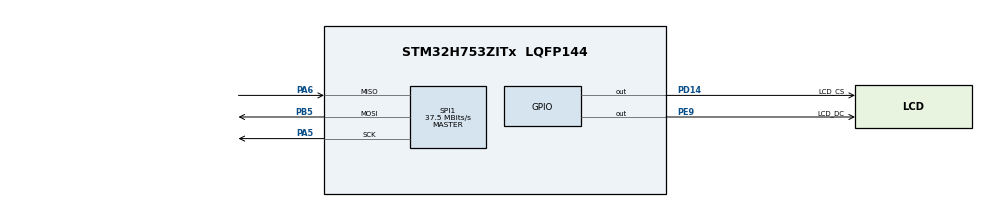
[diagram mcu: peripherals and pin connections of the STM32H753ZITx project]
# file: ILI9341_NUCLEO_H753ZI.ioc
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CORTEX_M7.CPU_DCache=Disabled
CORTEX_M7.CPU_ICache=Disabled
CORTEX_M7.MPU_Control=__NULL
CORTEX_M7.default_mode_Activation=1
Mcu.Family=STM32H7
Mcu.Name=STM32H753ZITx
Mcu.Package=LQFP144
NUCLEO-H753ZI.VCP=true
NVIC.PriorityGroup=NVIC_PRIORITYGROUP_4
NVIC.TIM6_DAC_IRQn=true\:0\:0\:false\:false\:true\:true\:true\:true
PA5.Mode=Full_Duplex_Master
PA5.Signal=SPI1_SCK
PA6.Mode=Full_Duplex_Master
PA6.Signal=SPI1_MISO
PB5.Mode=Full_Duplex_Master
PB5.Signal=SPI1_MOSI
PC14-OSC32_IN\ (OSC32_IN).Signal=RCC_OSC32_IN
PC15-OSC32_OUT\ (OSC32_OUT).Signal=RCC_OSC32_OUT
PD14.GPIO_Label=LCD_CS
PD14.Signal=GPIO_Output
PD8.Signal=USART3_TX
PD9.Signal=USART3_RX
PE9.GPIO_Label=LCD_DC
PE9.Signal=GPIO_Output
PH0-OSC_IN\ (PH0).Signal=RCC_OSC_IN
PH1-OSC_OUT\ (PH1).Signal=RCC_OSC_OUT
ProjectManager.HeapSize=0x200
ProjectManager.StackSize=0x400
ProjectManager.TargetToolchain=STM32CubeIDE
RCC.ADCFreq_Value=129000000
RCC.APB1Freq_Value=64000000
RCC.APB2Freq_Value=64000000
RCC.APB3Freq_Value=64000000
RCC.APB4Freq_Value=64000000
RCC.CortexFreq_Value=64000000
RCC.DIVM1=4
RCC.DIVN1=9
RCC.DIVQ1=1
RCC.HCLKFreq_Value=64000000
RCC.HSE_VALUE=8000000
RCC.PLLFRACN=3072
RCC.PWR_Regulator_Voltage_Scale=PWR_REGULATOR_VOLTAGE_SCALE2
RCC.SYSCLKFreq_VALUE=64000000
RCC.USBFreq_Value=150000000
SPI1.BaudRatePrescaler=SPI_BAUDRATEPRESCALER_4
SPI1.CalculateBaudRate=37.5 MBits/s
SPI1.DataSize=SPI_DATASIZE_8BIT
SPI1.Direction=SPI_DIRECTION_2LINES
SPI1.MasterKeepIOState=SPI_MASTER_KEEP_IO_STATE_ENABLE
SPI1.MasterReceiverAutoSusp=SPI_MASTER_RX_AUTOSUSP_ENABLE
SPI1.Mode=SPI_MODE_MASTER
SPI1.NSSPMode=SPI_NSS_PULSE_DISABLE
SPI1.VirtualType=VM_MASTER
TIM6.Period=999
TIM6.Prescaler=63
VP_MEMORYMAP_VS_MEMORYMAP.Mode=CurAppReg
VP_NUCLEO-H753ZI_VS_BSP_COMMON.Mode=COMMON
VP_TIM6_VS_ClockSourceINT.Mode=Enable_Timer
board=NUCLEO-H753ZI

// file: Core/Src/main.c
/* USER CODE BEGIN Header */
/**
  ******************************************************************************
  * @file           : main.c
  * @brief          : Main program body
  ******************************************************************************
  * @attention
  *
  * Copyright (c) 2026 STMicroelectronics.
  * All rights reserved.
  *
  * This software is licensed under terms that can be found in the LICENSE file
  * in the root directory of this software component.
  * If no LICENSE file comes with this software, it is provided AS-IS.
  *
  ******************************************************************************
  */
/* USER CODE END Header */
#include "main.h"

/* USER CODE BEGIN Includes */

#include "ili9341.h"

#include "lvgl.h"
#include "demos/lv_demos.h"

/* USER CODE END Includes */

/* USER CODE BEGIN PM */

#define LCD_WIDTH             	320
#define LCD_HEIGHT            	240

#define CHUNK_SIZE (LCD_HEIGHT * LCD_WIDTH / 3)

#define LCD_FB_BYTE_PER_PIXEL 	2
/* Max DMA transfer = 65535 bytes (uint16_t). 320*102*2 = 65280 bytes. */
#define LCD_VIRTUAL_BUF_SIZE (LCD_WIDTH * 102)

// RGB565 color format: 16-bit
#define COLOR_RED   0xF800
#define COLOR_BLUE  0x001F

/* USER CODE END PM */

COM_InitTypeDef BspCOMInit;

SPI_HandleTypeDef hspi1;

TIM_HandleTypeDef htim6;

/* USER CODE BEGIN PV */

uint8_t buffer[CHUNK_SIZE];

/* Align to 32 bytes for D-Cache / DMA coherency */
static uint8_t s_frameBuffer[2][LCD_VIRTUAL_BUF_SIZE * LCD_FB_BYTE_PER_PIXEL] __attribute__((aligned(32)));

/* USER CODE END PV */

void SystemClock_Config(void);
static void MX_GPIO_Init(void);
static void MX_SPI1_Init(void);
static void MX_TIM6_Init(void);
/* USER CODE BEGIN PFP */

void LCD_Init();
void LCD_Test();

#ifdef __cplusplus
extern "C" {
#endif

void lv_port_disp_init(void);
void lv_port_indev_init(void);

#if defined(__cplusplus)
}
#endif

/* USER CODE END PFP */

int main(void)
{

  /* USER CODE BEGIN 1 */
  SCB_EnableICache();
  SCB_EnableDCache();
  /* USER CODE END 1 */

  /* MCU Configuration--------------------------------------------------------*/

  /* Reset of all peripherals, Initializes the Flash interface and the Systick. */
  HAL_Init();

  /* Configure the system clock */
  SystemClock_Config();

  /* Initialize all configured peripherals */
  MX_GPIO_Init();
  MX_SPI1_Init();
  MX_TIM6_Init();
  /* USER CODE BEGIN 2 */

  HAL_TIM_Base_Start_IT(&htim6);

  LCD_Init();

  lv_init();
  lv_port_disp_init();

  /* USER CODE END 2 */

  /* Initialize COM1 port (115200, 8 bits (7-bit data + 1 stop bit), no parity */
  BspCOMInit.BaudRate   = 115200;
  BspCOMInit.WordLength = COM_WORDLENGTH_8B;
  BspCOMInit.StopBits   = COM_STOPBITS_1;
  BspCOMInit.Parity     = COM_PARITY_NONE;
  BspCOMInit.HwFlowCtl  = COM_HWCONTROL_NONE;
  if (BSP_COM_Init(COM1, &BspCOMInit) != BSP_ERROR_NONE)
  {
    Error_Handler();
  }

  /* Infinite loop */
  while (1)
  {

    /* USER CODE BEGIN 3 */
	//LCD_Test();
	//HAL_Delay(1000);

	// LVGL Demo,
	/* enable the flag also in lv_conf.h */
	//lv_demo_widgets();
	//lv_demo_stress();
	lv_demo_music();

	for (;;)
	{
		lv_timer_handler();
	}
  }
  /* USER CODE END 3 */
}

void SystemClock_Config(void)
{
  RCC_OscInitTypeDef RCC_OscInitStruct = {0};
  RCC_ClkInitTypeDef RCC_ClkInitStruct = {0};

  /** Supply configuration update enable
  */
  HAL_PWREx_ConfigSupply(PWR_LDO_SUPPLY);

  /** Configure the main internal regulator output voltage
   *  VOS1 first (required step before VOS0 on some revisions)
  */
  __HAL_PWR_VOLTAGESCALING_CONFIG(PWR_REGULATOR_VOLTAGE_SCALE1);
  while(!__HAL_PWR_GET_FLAG(PWR_FLAG_VOSRDY)) {}

  /** Enable VOS0 (overdrive) for 480 MHz operation */
  HAL_PWREx_ControlVoltageScaling(PWR_REGULATOR_VOLTAGE_SCALE0);
  while(!__HAL_PWR_GET_FLAG(PWR_FLAG_VOSRDY)) {}

  /** PLL1 configuration:
   *  HSI = 64 MHz
   *  VCO input  = 64 / PLLM(4)  = 16 MHz   (range 8-16 MHz)
   *  VCO output = 16 * PLLN(60) = 960 MHz   (wide range 192-960 MHz)
   *  PLLP = 960 / 2 = 480 MHz  -> SYSCLK
   *  PLLQ = 960 / 4 = 240 MHz  -> SPI1 kernel clock
   */
  RCC_OscInitStruct.OscillatorType = RCC_OSCILLATORTYPE_HSI;
  RCC_OscInitStruct.HSIState = RCC_HSI_DIV1;
  RCC_OscInitStruct.HSICalibrationValue = RCC_HSICALIBRATION_DEFAULT;
  RCC_OscInitStruct.PLL.PLLState = RCC_PLL_ON;
  RCC_OscInitStruct.PLL.PLLSource = RCC_PLLSOURCE_HSI;
  RCC_OscInitStruct.PLL.PLLM = 4;
  RCC_OscInitStruct.PLL.PLLN = 60;
  RCC_OscInitStruct.PLL.PLLP = 2;
  RCC_OscInitStruct.PLL.PLLQ = 4;
  RCC_OscInitStruct.PLL.PLLR = 2;
  RCC_OscInitStruct.PLL.PLLRGE = RCC_PLL1VCIRANGE_3;
  RCC_OscInitStruct.PLL.PLLVCOSEL = RCC_PLL1VCOWIDE;
  RCC_OscInitStruct.PLL.PLLFRACN = 0;
  if (HAL_RCC_OscConfig(&RCC_OscInitStruct) != HAL_OK)
  {
    Error_Handler();
  }

  /** Initializes the CPU, AHB and APB buses clocks
   *  SYSCLK = 480 MHz (PLL1P)
   *  AHB    = 240 MHz (SYSCLK / 2)
   *  APB1   = 120 MHz (AHB / 2)
   *  APB2   = 120 MHz (AHB / 2)
   *  APB3   = 120 MHz (AHB / 2)
   *  APB4   = 120 MHz (AHB / 2)
  */
  RCC_ClkInitStruct.ClockType = RCC_CLOCKTYPE_HCLK|RCC_CLOCKTYPE_SYSCLK
                              |RCC_CLOCKTYPE_PCLK1|RCC_CLOCKTYPE_PCLK2
                              |RCC_CLOCKTYPE_D3PCLK1|RCC_CLOCKTYPE_D1PCLK1;
  RCC_ClkInitStruct.SYSCLKSource = RCC_SYSCLKSOURCE_PLLCLK;
  RCC_ClkInitStruct.SYSCLKDivider = RCC_SYSCLK_DIV1;
  RCC_ClkInitStruct.AHBCLKDivider = RCC_HCLK_DIV2;
  RCC_ClkInitStruct.APB3CLKDivider = RCC_APB3_DIV2;
  RCC_ClkInitStruct.APB1CLKDivider = RCC_APB1_DIV2;
  RCC_ClkInitStruct.APB2CLKDivider = RCC_APB2_DIV2;
  RCC_ClkInitStruct.APB4CLKDivider = RCC_APB4_DIV2;

  if (HAL_RCC_ClockConfig(&RCC_ClkInitStruct, FLASH_LATENCY_4) != HAL_OK)
  {
    Error_Handler();
  }
}

static void MX_SPI1_Init(void)
{

  /* SPI1 parameter configuration*/
  hspi1.Instance = SPI1;
  hspi1.Init.Mode = SPI_MODE_MASTER;
  hspi1.Init.Direction = SPI_DIRECTION_2LINES;
  hspi1.Init.DataSize = SPI_DATASIZE_8BIT;
  hspi1.Init.CLKPolarity = SPI_POLARITY_LOW;
  hspi1.Init.CLKPhase = SPI_PHASE_1EDGE;
  hspi1.Init.NSS = SPI_NSS_SOFT;
  hspi1.Init.BaudRatePrescaler = SPI_BAUDRATEPRESCALER_4;
  hspi1.Init.FirstBit = SPI_FIRSTBIT_MSB;
  hspi1.Init.TIMode = SPI_TIMODE_DISABLE;
  hspi1.Init.CRCCalculation = SPI_CRCCALCULATION_DISABLE;
  hspi1.Init.CRCPolynomial = 0x0;
  hspi1.Init.NSSPMode = SPI_NSS_PULSE_DISABLE;
  hspi1.Init.NSSPolarity = SPI_NSS_POLARITY_LOW;
  hspi1.Init.FifoThreshold = SPI_FIFO_THRESHOLD_08DATA;
  hspi1.Init.TxCRCInitializationPattern = SPI_CRC_INITIALIZATION_ALL_ZERO_PATTERN;
  hspi1.Init.RxCRCInitializationPattern = SPI_CRC_INITIALIZATION_ALL_ZERO_PATTERN;
  hspi1.Init.MasterSSIdleness = SPI_MASTER_SS_IDLENESS_00CYCLE;
  hspi1.Init.MasterInterDataIdleness = SPI_MASTER_INTERDATA_IDLENESS_00CYCLE;
  hspi1.Init.MasterReceiverAutoSusp = SPI_MASTER_RX_AUTOSUSP_ENABLE;
  hspi1.Init.MasterKeepIOState = SPI_MASTER_KEEP_IO_STATE_ENABLE;
  hspi1.Init.IOSwap = SPI_IO_SWAP_DISABLE;
  if (HAL_SPI_Init(&hspi1) != HAL_OK)
  {
    Error_Handler();
  }

}

static void MX_TIM6_Init(void)
{

  TIM_MasterConfigTypeDef sMasterConfig = {0};

  htim6.Instance = TIM6;
  htim6.Init.Prescaler = 239;
  htim6.Init.CounterMode = TIM_COUNTERMODE_UP;
  htim6.Init.Period = 999;
  htim6.Init.AutoReloadPreload = TIM_AUTORELOAD_PRELOAD_DISABLE;
  if (HAL_TIM_Base_Init(&htim6) != HAL_OK)
  {
    Error_Handler();
  }
  sMasterConfig.MasterOutputTrigger = TIM_TRGO_RESET;
  sMasterConfig.MasterSlaveMode = TIM_MASTERSLAVEMODE_DISABLE;
  if (HAL_TIMEx_MasterConfigSynchronization(&htim6, &sMasterConfig) != HAL_OK)
  {
    Error_Handler();
  }

}

static void MX_GPIO_Init(void)
{
  GPIO_InitTypeDef GPIO_InitStruct = {0};

  /* GPIO Ports Clock Enable */
  __HAL_RCC_GPIOC_CLK_ENABLE();
  __HAL_RCC_GPIOH_CLK_ENABLE();
  __HAL_RCC_GPIOA_CLK_ENABLE();
  __HAL_RCC_GPIOE_CLK_ENABLE();
  __HAL_RCC_GPIOD_CLK_ENABLE();
  __HAL_RCC_GPIOB_CLK_ENABLE();

  /*Configure GPIO pin Output Level */
  HAL_GPIO_WritePin(LCD_DC_GPIO_Port, LCD_DC_Pin, GPIO_PIN_RESET);

  /*Configure GPIO pin Output Level */
  HAL_GPIO_WritePin(LCD_CS_GPIO_Port, LCD_CS_Pin, GPIO_PIN_RESET);

  /*Configure GPIO pin : LCD_DC_Pin */
  GPIO_InitStruct.Pin = LCD_DC_Pin;
  GPIO_InitStruct.Mode = GPIO_MODE_OUTPUT_PP;
  GPIO_InitStruct.Pull = GPIO_NOPULL;
  GPIO_InitStruct.Speed = GPIO_SPEED_FREQ_VERY_HIGH;
  HAL_GPIO_Init(LCD_DC_GPIO_Port, &GPIO_InitStruct);

  /*Configure GPIO pin : LCD_CS_Pin */
  GPIO_InitStruct.Pin = LCD_CS_Pin;
  GPIO_InitStruct.Mode = GPIO_MODE_OUTPUT_PP;
  GPIO_InitStruct.Pull = GPIO_NOPULL;
  GPIO_InitStruct.Speed = GPIO_SPEED_FREQ_VERY_HIGH;
  HAL_GPIO_Init(LCD_CS_GPIO_Port, &GPIO_InitStruct);

}

/* USER CODE BEGIN 4 */

/* LCD Support BEGIN */

/* Fast direct SPI transfer -- bypasses HAL lock/state/timeout overhead.
 * Only for small blocking command/data bytes, NOT for DMA pixel transfers.
 * Leaves SPI disabled + flags cleared so HAL_SPI_Transmit_DMA works after. */
static inline void SPI1_SendBlocking(const uint8_t *data, uint32_t len)
{
    MODIFY_REG(SPI1->CR2, SPI_CR2_TSIZE, len);
    SET_BIT(SPI1->CR1, SPI_CR1_SPE);
    SET_BIT(SPI1->CR1, SPI_CR1_CSTART);
    for (uint32_t i = 0; i < len; i++)
    {
        while (!(SPI1->SR & SPI_SR_TXP));
        *(volatile uint8_t *)&SPI1->TXDR = data[i];
    }
    while (!(SPI1->SR & SPI_SR_EOT));
    SET_BIT(SPI1->IFCR, SPI_IFCR_EOTC | SPI_IFCR_TXTFC);
    CLEAR_BIT(SPI1->CR1, SPI_CR1_SPE);
}

void LCD_WriteCmd(uint8_t cmd)
{
    LCD_DC_GPIO_Port->BSRR = (uint32_t)LCD_DC_Pin << 16U; /* DC low */
    SPI1_SendBlocking(&cmd, 1);
}

void LCD_WriteData(uint8_t cmd)
{
    LCD_DC_GPIO_Port->BSRR = LCD_DC_Pin; /* DC high */
    SPI1_SendBlocking(&cmd, 1);
}

void LCD_WriteMultiData(uint8_t *data, size_t length)
{
    LCD_DC_GPIO_Port->BSRR = LCD_DC_Pin; /* DC high */
    SPI1_SendBlocking(data, length);
}

static void LCD_SetAddressWindow(uint16_t x0, uint16_t y0, uint16_t x1, uint16_t y1)
{
    LCD_WriteCmd(0x2A); // Column addr set
    LCD_WriteData(x0 >> 8);
    LCD_WriteData(x0 & 0xFF);
    LCD_WriteData(x1 >> 8);
    LCD_WriteData(x1 & 0xFF);

    LCD_WriteCmd(0x2B); // Row addr set
    LCD_WriteData(y0 >> 8);
    LCD_WriteData(y0 & 0xFF);
    LCD_WriteData(y1 >> 8);
    LCD_WriteData(y1 & 0xFF);

    LCD_WriteCmd(0x2C); // Write to RAM
}

void LCD_FillScreen(uint16_t color)
{
	// Fill buffer with repeated color value
	for (int i = 0; i < CHUNK_SIZE; i += 2)
	{
		buffer[i] = color >> 8;
		buffer[i + 1] = color & 0xFF;
	}

	// Set window to full screen
	LCD_SetAddressWindow(0, 0, LCD_WIDTH - 1, LCD_HEIGHT - 1);

	// Total number of pixels to send
	uint32_t totalBytes = LCD_WIDTH * LCD_HEIGHT * 2;
	while (totalBytes > 0)
	{
		uint32_t sendSize = (totalBytes > CHUNK_SIZE) ? CHUNK_SIZE : totalBytes;
		LCD_WriteMultiData(buffer, sendSize);
		totalBytes -= sendSize;
	}
}
void LCD_Init()
{
	HAL_GPIO_WritePin(LCD_CS_GPIO_Port, LCD_CS_Pin, GPIO_PIN_RESET);

	/* Set the initialization register */
	ILI9341_Init(LCD_WriteData, LCD_WriteCmd);

	/* Change to landscape view. */
	LCD_WriteCmd(ILI9341_CMD_MAC);
	LCD_WriteData(0x28);
}
void LCD_Test(){
	LCD_FillScreen(COLOR_RED);
	LCD_FillScreen(COLOR_BLUE);
}

static volatile lv_display_t *s_flushDisp = NULL;

static void LCD_FlushDisplay(lv_display_t *disp_drv, const lv_area_t *area, uint8_t *color_p)
{

    lv_coord_t x1 = area->x1;
    lv_coord_t y1 = area->y1;
    lv_coord_t x2 = area->x2;
    lv_coord_t y2 = area->y2;

    uint8_t data[4];
    uint32_t send_size   = (x2 - x1 + 1) * (y2 - y1 + 1) * LCD_FB_BYTE_PER_PIXEL;

    /*Column addresses*/
    LCD_WriteCmd(ILI9341_CMD_COLADDR);
    data[0] = (x1 >> 8) & 0xFF;
    data[1] = x1 & 0xFF;
    data[2] = (x2 >> 8) & 0xFF;
    data[3] = x2 & 0xFF;
    LCD_WriteMultiData(data, 4);

    /*Page addresses*/
    LCD_WriteCmd(ILI9341_CMD_PAGEADDR);
    data[0] = (y1 >> 8) & 0xFF;
    data[1] = y1 & 0xFF;
    data[2] = (y2 >> 8) & 0xFF;
    data[3] = y2 & 0xFF;
    LCD_WriteMultiData(data, 4);

    /*Memory write via DMA*/
    LCD_WriteCmd(ILI9341_CMD_GRAM);
    LCD_DC_GPIO_Port->BSRR = LCD_DC_Pin; /* DC high */

    /* Flush D-Cache so DMA sees the correct data */
    SCB_CleanDCache_by_Addr((uint32_t *)((uint32_t)color_p & ~31U),
                            send_size + 32);

    s_flushDisp = disp_drv;
    HAL_SPI_Transmit_DMA(&hspi1, color_p, send_size);
    /* lv_disp_flush_ready() will be called from HAL_SPI_TxCpltCallback */
}

void HAL_SPI_TxCpltCallback(SPI_HandleTypeDef *hspi)
{
    if (hspi->Instance == SPI1 && s_flushDisp != NULL)
    {
        lv_disp_flush_ready((lv_display_t *)s_flushDisp);
        s_flushDisp = NULL;
    }
}

void lv_port_disp_init(void)
{
    lv_display_t * disp_drv; /*Descriptor of a display driver*/

    /*-------------------------
     * Initialize your display
     * -----------------------*/
    LCD_Init();

    disp_drv = lv_display_create(LCD_WIDTH, LCD_HEIGHT);

    lv_display_set_buffers(
    		disp_drv,
    		s_frameBuffer[0],
			s_frameBuffer[1],
			sizeof(s_frameBuffer[0]),
			LV_DISPLAY_RENDER_MODE_PARTIAL);
    lv_display_set_flush_cb(disp_drv, LCD_FlushDisplay);
}
/* LCD Support END */

void HAL_TIM_PeriodElapsedCallback(TIM_HandleTypeDef *htim)
{
    if (htim->Instance == TIM6)
    {
        lv_tick_inc(1);
    }
}
/* USER CODE END 4 */

void Error_Handler(void)
{
  __disable_irq();
  while (1)
  {
  }
}
